VERSION 5.7 ;
  NOWIREEXTENSIONATPIN ON ;
  DIVIDERCHAR "/" ;
  BUSBITCHARS "[]" ;
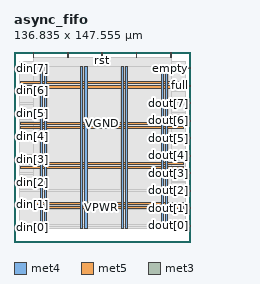
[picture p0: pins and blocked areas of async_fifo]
MACRO async_fifo
  CLASS BLOCK ;
  FOREIGN async_fifo ;
  ORIGIN 0.000 0.000 ;
  SIZE 136.835 BY 147.555 ;
  PIN VGND
    DIRECTION INOUT ;
    USE GROUND ;
    PORT
      LAYER met4 ;
        RECT 23.715 10.640 25.315 136.240 ;
    END
    PORT
      LAYER met4 ;
        RECT 55.110 10.640 56.710 136.240 ;
    END
    PORT
      LAYER met4 ;
        RECT 86.505 10.640 88.105 136.240 ;
    END
    PORT
      LAYER met4 ;
        RECT 117.900 10.640 119.500 136.240 ;
    END
    PORT
      LAYER met5 ;
        RECT 5.280 29.020 131.340 30.620 ;
    END
    PORT
      LAYER met5 ;
        RECT 5.280 60.300 131.340 61.900 ;
    END
    PORT
      LAYER met5 ;
        RECT 5.280 91.580 131.340 93.180 ;
    END
    PORT
      LAYER met5 ;
        RECT 5.280 122.860 131.340 124.460 ;
    END
  END VGND
  PIN VPWR
    DIRECTION INOUT ;
    USE POWER ;
    PORT
      LAYER met4 ;
        RECT 20.415 10.640 22.015 136.240 ;
    END
    PORT
      LAYER met4 ;
        RECT 51.810 10.640 53.410 136.240 ;
    END
    PORT
      LAYER met4 ;
        RECT 83.205 10.640 84.805 136.240 ;
    END
    PORT
      LAYER met4 ;
        RECT 114.600 10.640 116.200 136.240 ;
    END
    PORT
      LAYER met5 ;
        RECT 5.280 25.720 131.340 27.320 ;
    END
    PORT
      LAYER met5 ;
        RECT 5.280 57.000 131.340 58.600 ;
    END
    PORT
      LAYER met5 ;
        RECT 5.280 88.280 131.340 89.880 ;
    END
    PORT
      LAYER met5 ;
        RECT 5.280 119.560 131.340 121.160 ;
    END
  END VPWR
  PIN din[0]
    DIRECTION INPUT ;
    USE SIGNAL ;
    ANTENNAGATEAREA 0.213000 ;
    PORT
      LAYER met3 ;
        RECT 0.000 10.920 4.000 11.520 ;
    END
  END din[0]
  PIN din[1]
    DIRECTION INPUT ;
    USE SIGNAL ;
    ANTENNAGATEAREA 0.213000 ;
    PORT
      LAYER met3 ;
        RECT 0.000 28.600 4.000 29.200 ;
    END
  END din[1]
  PIN din[2]
    DIRECTION INPUT ;
    USE SIGNAL ;
    ANTENNAGATEAREA 0.213000 ;
    PORT
      LAYER met3 ;
        RECT 0.000 46.280 4.000 46.880 ;
    END
  END din[2]
  PIN din[3]
    DIRECTION INPUT ;
    USE SIGNAL ;
    ANTENNAGATEAREA 0.213000 ;
    PORT
      LAYER met3 ;
        RECT 0.000 63.960 4.000 64.560 ;
    END
  END din[3]
  PIN din[4]
    DIRECTION INPUT ;
    USE SIGNAL ;
    ANTENNAGATEAREA 0.213000 ;
    PORT
      LAYER met3 ;
        RECT 0.000 81.640 4.000 82.240 ;
    END
  END din[4]
  PIN din[5]
    DIRECTION INPUT ;
    USE SIGNAL ;
    ANTENNAGATEAREA 0.213000 ;
    PORT
      LAYER met3 ;
        RECT 0.000 99.320 4.000 99.920 ;
    END
  END din[5]
  PIN din[6]
    DIRECTION INPUT ;
    USE SIGNAL ;
    ANTENNAGATEAREA 0.213000 ;
    PORT
      LAYER met3 ;
        RECT 0.000 117.000 4.000 117.600 ;
    END
  END din[6]
  PIN din[7]
    DIRECTION INPUT ;
    USE SIGNAL ;
    ANTENNAGATEAREA 0.213000 ;
    PORT
      LAYER met3 ;
        RECT 0.000 134.680 4.000 135.280 ;
    END
  END din[7]
  PIN dout[0]
    DIRECTION OUTPUT TRISTATE ;
    USE SIGNAL ;
    ANTENNADIFFAREA 0.340600 ;
    PORT
      LAYER met3 ;
        RECT 132.835 12.280 136.835 12.880 ;
    END
  END dout[0]
  PIN dout[1]
    DIRECTION OUTPUT TRISTATE ;
    USE SIGNAL ;
    ANTENNADIFFAREA 0.340600 ;
    PORT
      LAYER met3 ;
        RECT 132.835 25.880 136.835 26.480 ;
    END
  END dout[1]
  PIN dout[2]
    DIRECTION OUTPUT TRISTATE ;
    USE SIGNAL ;
    ANTENNADIFFAREA 0.340600 ;
    PORT
      LAYER met3 ;
        RECT 132.835 39.480 136.835 40.080 ;
    END
  END dout[2]
  PIN dout[3]
    DIRECTION OUTPUT TRISTATE ;
    USE SIGNAL ;
    ANTENNADIFFAREA 0.340600 ;
    PORT
      LAYER met3 ;
        RECT 132.835 53.080 136.835 53.680 ;
    END
  END dout[3]
  PIN dout[4]
    DIRECTION OUTPUT TRISTATE ;
    USE SIGNAL ;
    ANTENNADIFFAREA 0.340600 ;
    PORT
      LAYER met3 ;
        RECT 132.835 66.680 136.835 67.280 ;
    END
  END dout[4]
  PIN dout[5]
    DIRECTION OUTPUT TRISTATE ;
    USE SIGNAL ;
    ANTENNADIFFAREA 0.340600 ;
    PORT
      LAYER met3 ;
        RECT 132.835 80.280 136.835 80.880 ;
    END
  END dout[5]
  PIN dout[6]
    DIRECTION OUTPUT TRISTATE ;
    USE SIGNAL ;
    ANTENNADIFFAREA 0.340600 ;
    PORT
      LAYER met3 ;
        RECT 132.835 93.880 136.835 94.480 ;
    END
  END dout[6]
  PIN dout[7]
    DIRECTION OUTPUT TRISTATE ;
    USE SIGNAL ;
    ANTENNADIFFAREA 0.340600 ;
    PORT
      LAYER met3 ;
        RECT 132.835 107.480 136.835 108.080 ;
    END
  END dout[7]
  PIN empty
    DIRECTION OUTPUT TRISTATE ;
    USE SIGNAL ;
    ANTENNADIFFAREA 0.340600 ;
    PORT
      LAYER met3 ;
        RECT 132.835 134.680 136.835 135.280 ;
    END
  END empty
  PIN full
    DIRECTION OUTPUT TRISTATE ;
    USE SIGNAL ;
    ANTENNADIFFAREA 0.340600 ;
    PORT
      LAYER met3 ;
        RECT 132.835 121.080 136.835 121.680 ;
    END
  END full
  PIN rd_clk
    DIRECTION INPUT ;
    USE SIGNAL ;
    ANTENNAGATEAREA 0.852000 ;
    PORT
      LAYER met4 ;
        RECT 94.920 143.555 95.520 147.555 ;
    END
  END rd_clk
  PIN rd_en
    DIRECTION INPUT ;
    USE SIGNAL ;
    ANTENNAGATEAREA 0.196500 ;
    PORT
      LAYER met4 ;
        RECT 121.600 143.555 122.200 147.555 ;
    END
  END rd_en
  PIN rst
    DIRECTION INPUT ;
    USE SIGNAL ;
    ANTENNAGATEAREA 0.742500 ;
    PORT
      LAYER met4 ;
        RECT 68.240 143.555 68.840 147.555 ;
    END
  END rst
  PIN wr_clk
    DIRECTION INPUT ;
    USE SIGNAL ;
    ANTENNAGATEAREA 0.852000 ;
    PORT
      LAYER met4 ;
        RECT 14.880 143.555 15.480 147.555 ;
    END
  END wr_clk
  PIN wr_en
    DIRECTION INPUT ;
    USE SIGNAL ;
    ANTENNAGATEAREA 0.196500 ;
    PORT
      LAYER met4 ;
        RECT 41.560 143.555 42.160 147.555 ;
    END
  END wr_en
  OBS
      LAYER li1 ;
        RECT 5.520 10.795 131.100 136.085 ;
      LAYER met1 ;
        RECT 4.670 10.640 131.950 136.240 ;
      LAYER met2 ;
        RECT 4.690 10.695 131.930 139.925 ;
      LAYER met3 ;
        RECT 4.000 135.680 132.835 139.905 ;
        RECT 4.400 134.280 132.435 135.680 ;
        RECT 4.000 122.080 132.835 134.280 ;
        RECT 4.000 120.680 132.435 122.080 ;
        RECT 4.000 118.000 132.835 120.680 ;
        RECT 4.400 116.600 132.835 118.000 ;
        RECT 4.000 108.480 132.835 116.600 ;
        RECT 4.000 107.080 132.435 108.480 ;
        RECT 4.000 100.320 132.835 107.080 ;
        RECT 4.400 98.920 132.835 100.320 ;
        RECT 4.000 94.880 132.835 98.920 ;
        RECT 4.000 93.480 132.435 94.880 ;
        RECT 4.000 82.640 132.835 93.480 ;
        RECT 4.400 81.280 132.835 82.640 ;
        RECT 4.400 81.240 132.435 81.280 ;
        RECT 4.000 79.880 132.435 81.240 ;
        RECT 4.000 67.680 132.835 79.880 ;
        RECT 4.000 66.280 132.435 67.680 ;
        RECT 4.000 64.960 132.835 66.280 ;
        RECT 4.400 63.560 132.835 64.960 ;
        RECT 4.000 54.080 132.835 63.560 ;
        RECT 4.000 52.680 132.435 54.080 ;
        RECT 4.000 47.280 132.835 52.680 ;
        RECT 4.400 45.880 132.835 47.280 ;
        RECT 4.000 40.480 132.835 45.880 ;
        RECT 4.000 39.080 132.435 40.480 ;
        RECT 4.000 29.600 132.835 39.080 ;
        RECT 4.400 28.200 132.835 29.600 ;
        RECT 4.000 26.880 132.835 28.200 ;
        RECT 4.000 25.480 132.435 26.880 ;
        RECT 4.000 13.280 132.835 25.480 ;
        RECT 4.000 11.920 132.435 13.280 ;
        RECT 4.400 11.880 132.435 11.920 ;
        RECT 4.400 10.715 132.835 11.880 ;
      LAYER met4 ;
        RECT 15.880 143.155 41.160 143.555 ;
        RECT 42.560 143.155 67.840 143.555 ;
        RECT 69.240 143.155 94.520 143.555 ;
        RECT 95.920 143.155 121.200 143.555 ;
        RECT 15.015 136.640 122.065 143.155 ;
        RECT 15.015 40.975 20.015 136.640 ;
        RECT 22.415 40.975 23.315 136.640 ;
        RECT 25.715 40.975 51.410 136.640 ;
        RECT 53.810 40.975 54.710 136.640 ;
        RECT 57.110 40.975 82.805 136.640 ;
        RECT 85.205 40.975 86.105 136.640 ;
        RECT 88.505 40.975 114.200 136.640 ;
        RECT 116.600 40.975 117.500 136.640 ;
        RECT 119.900 40.975 122.065 136.640 ;
  END
END async_fifo
END LIBRARY

